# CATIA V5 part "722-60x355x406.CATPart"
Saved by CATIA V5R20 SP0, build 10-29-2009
Part number: 722-60x355x406
Definition: NONE
Nomenclature: 722-60x355x406
Source: Unknown
Description: 722-60x355x406
Bounding box of the stored display mesh (mm): x -30 to 30, y -30 to 30, z -337 to 69
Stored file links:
  C:\Users\Utente\Desktop\IO LAVORO\3D X SITO CF\X SITO\722\722-60x355x406.CATPart

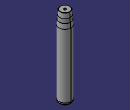
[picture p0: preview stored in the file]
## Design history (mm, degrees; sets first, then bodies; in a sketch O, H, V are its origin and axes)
Body1 "722-60x355x406" (main body)
  Solid1: solid without history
